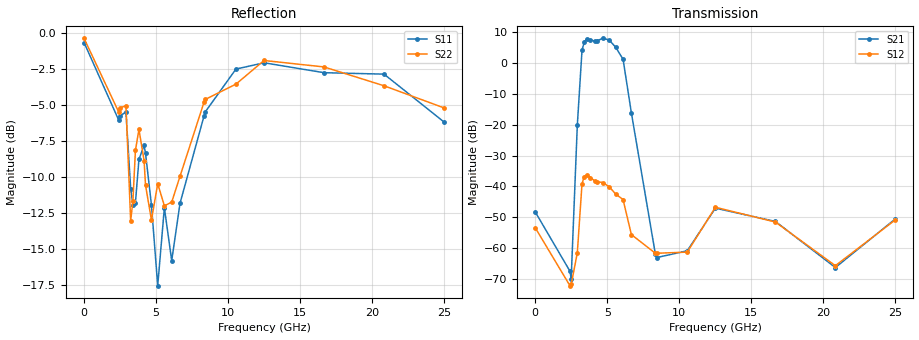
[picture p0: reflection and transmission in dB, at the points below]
!Agilent Technologies,E8364B,MY43040894,A.07.50.67
!Agilent E8364B: A.07.50.67
!Date: Wednesday, July 07, 2021 13:19:26
!Correction: S11(Full 2 Port(1,2))
!S21(Full 2 Port(1,2))
!S12(Full 2 Port(1,2))
!S22(Full 2 Port(1,2))
!S2P File: Measurements: S11, S21, S12, S22:
# Hz S  dB  R 50
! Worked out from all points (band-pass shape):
!   8001 points, 10 MHz to 25 GHz, reference 50 ohm
!   highest |S21| = 8.03 dB at 4.689 GHz (marker M1); lowest = -69.9 dB at 2.493 GHz (marker M2)
!   |S21| within 3 dB of the highest: 3.28 GHz to 5.6 GHz (2.32 GHz wide, 52.3 % of centre)
!   lowest |S11| = -17.6 dB at 5.124 GHz (marker M3), VSWR 1.31, Z = 38.4 - j1.12 ohm
!   |S11| at or under -10 dB: 3.183 GHz to 3.724 GHz (541.3 MHz wide, 15.7 % of centre); 4.48 GHz to 7.176 GHz (2.696 GHz wide, 46.3 % of centre)
!   |S22| runs from -14.7 to -0.3 dB; largest |S21 - S12| = 2.5
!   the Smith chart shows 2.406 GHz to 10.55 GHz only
!   S11 on the Smith chart (normalised r, x): 2.406 GHz: 1.05, +1.18; 2.918 GHz: 1.32, -1.41; 4.277 GHz: 0.47, -0.22; 6.673 GHz: 0.94, +0.51; 8.425 GHz: 0.79, -1.10; 10.55 GHz: 0.15, -0.25
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1e7  -0.63 -7.2  -48.36 -62.2  -53.49 57.5  -0.34 -7.8
2.405916e9  -6.01 57.8  -67.48 19.9  -72.19 -117.8  -5.45 60.2
2.493381e9  -5.75 42.6  -69.93 -3.6  -71.80 -108.0  -5.19 44.8
2.918211e9  -5.46 -46.0  -20.19 2.5  -61.57 -144.4  -5.02 -45.6
3.246205e9  -10.80 -85.4  4.24 153.5  -39.10 -8.7  -13.05 -80.7
3.402392e9  -11.94 -87.1  6.81 67.6  -36.79 -91.9  -11.64 -64.5
3.577322e9  -11.77 -84.2  7.72 -11.0  -36.32 -167.6  -8.13 -79.3
3.820975e9  -8.76 -96.3  7.54 -100.3  -37.10 107.2  -6.68 -112.5
4.177082e9  -7.79 -138.3  7.08 156.0  -38.34 9.5  -8.85 -157.8
4.277042e9  -8.34 -148.7  7.24 129.1  -38.44 -15.6  -10.56 -166.1
4.689378e9  -11.95 -178.2  8.03 13.0  -38.73 -120.7  -13.00 -145.3
5.123579e9  -17.56 -173.8  7.54 -113.6  -40.06 128.6  -10.46 -177.6
5.585894e9  -12.13 173.1  5.12 105.6  -42.48 7.3  -12.00 154.9
6.095065e9  -15.82 136.0  1.28 -67.0  -44.26 -146.4  -11.74 134.7
6.672959e9  -11.82 81.5  -16.15 70.3  -55.61 18.0  -9.94 73.0
8.341041e9  -5.74 -64.5  -62.01 -156.3  -61.68 -125.9  -4.78 -76.7
8.425382e9  -5.46 -69.2  -63.07 -163.1  -61.67 -134.4  -4.59 -81.6
1.055266e10  -2.48 -150.8  -60.87 152.0  -61.30 153.4  -3.53 -167.4
1.2505e10  -2.04 149.7  -47.04 102.1  -46.75 104.1  -1.88 136.9
1.667208e10  -2.73 22.1  -51.35 -76.3  -51.54 -78.2  -2.33 6.0
2.083604e10  -2.83 -70.0  -66.30 -65.0  -65.70 -31.0  -3.64 -81.8
2.5e10  -6.16 -114.6  -50.53 -77.2  -50.83 -72.9  -5.18 -122.6
